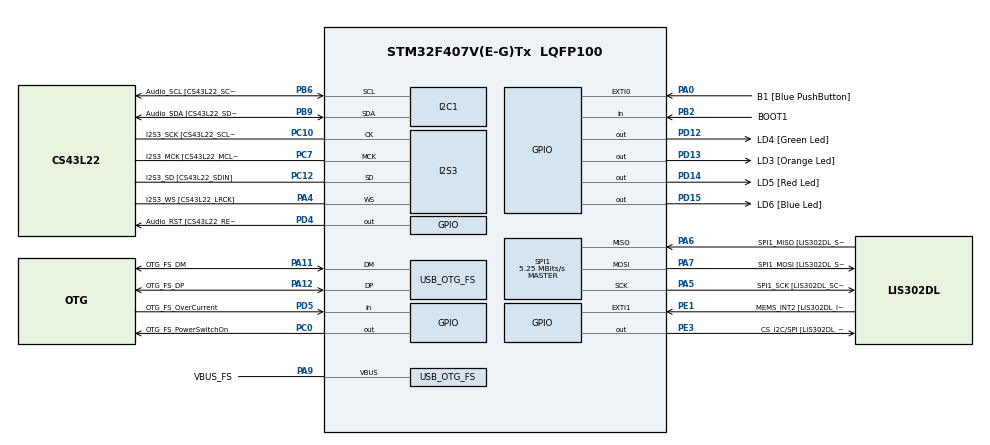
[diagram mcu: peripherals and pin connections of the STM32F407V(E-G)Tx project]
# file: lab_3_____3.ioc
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I2S3.AudioFreq-Half_Duplex_Master=I2S_AUDIOFREQ_96K
I2S3.ErrorAudioFreq=-2.34 %
I2S3.ErrorAudioFreq-Half_Duplex_Master=0.8 %
I2S3.FullDuplexMode=I2S_FULLDUPLEXMODE_DISABLE
I2S3.Instance=SPI$Index
I2S3.RealAudioFreq=93.75 KHz
I2S3.RealAudioFreq-Half_Duplex_Master=96.774 KHz
I2S3.VirtualMode=I2S_MODE_MASTER
Mcu.Family=STM32F4
Mcu.Name=STM32F407V(E-G)Tx
Mcu.Package=LQFP100
NVIC.OTG_FS_IRQn=true\:0\:0\:false\:false\:true\:true\:true
NVIC.PriorityGroup=NVIC_PRIORITYGROUP_0
NVIC.TIM2_IRQn=true\:0\:0\:false\:false\:true\:true\:true
NVIC.TIM3_IRQn=true\:0\:0\:false\:false\:true\:true\:true
NVIC.TIM4_IRQn=true\:0\:0\:false\:false\:true\:true\:true
PA0-WKUP.GPIO_Label=B1 [Blue PushButton]
PA0-WKUP.GPIO_ModeDefaultEXTI=GPIO_MODE_EVT_RISING
PA0-WKUP.GPIO_PuPd=GPIO_NOPULL
PA0-WKUP.Signal=GPXTI0
PA10.GPIO_Label=OTG_FS_ID
PA10.GPIO_Mode=GPIO_MODE_AF_PP
PA10.GPIO_PuPd=GPIO_NOPULL
PA10.GPIO_Speed=GPIO_SPEED_FREQ_LOW
PA10.Signal=USB_OTG_FS_ID
PA11.GPIO_Label=OTG_FS_DM
PA11.GPIO_Mode=GPIO_MODE_AF_PP
PA11.GPIO_PuPd=GPIO_NOPULL
PA11.GPIO_Speed=GPIO_SPEED_FREQ_LOW
PA11.Mode=Host_Only
PA11.Signal=USB_OTG_FS_DM
PA12.GPIO_Label=OTG_FS_DP
PA12.GPIO_Mode=GPIO_MODE_AF_PP
PA12.GPIO_PuPd=GPIO_NOPULL
PA12.GPIO_Speed=GPIO_SPEED_FREQ_LOW
PA12.Mode=Host_Only
PA12.Signal=USB_OTG_FS_DP
PA13.GPIO_Label=SWDIO
PA13.Mode=Serial_Wire
PA13.Signal=SYS_JTMS-SWDIO
PA14.GPIO_Label=SWCLK
PA14.Mode=Serial_Wire
PA14.Signal=SYS_JTCK-SWCLK
PA4.GPIO_Label=I2S3_WS [CS43L22_LRCK]
PA4.GPIO_Mode=GPIO_MODE_AF_PP
PA4.GPIO_PuPd=GPIO_NOPULL
PA4.GPIO_Speed=GPIO_SPEED_FREQ_LOW
PA4.Mode=Half_Duplex_Master
PA4.Signal=I2S3_WS
PA5.GPIO_Label=SPI1_SCK [LIS302DL_SCL/SPC]
PA5.GPIO_Mode=GPIO_MODE_AF_PP
PA5.GPIO_PuPd=GPIO_NOPULL
PA5.GPIO_Speed=GPIO_SPEED_FREQ_LOW
PA5.Mode=Full_Duplex_Master
PA5.Signal=SPI1_SCK
PA6.GPIO_Label=SPI1_MISO [LIS302DL_SDO]
PA6.GPIO_Mode=GPIO_MODE_AF_PP
PA6.GPIO_PuPd=GPIO_NOPULL
PA6.GPIO_Speed=GPIO_SPEED_FREQ_LOW
PA6.Mode=Full_Duplex_Master
PA6.Signal=SPI1_MISO
PA7.GPIO_Label=SPI1_MOSI [LIS302DL_SDA/SDI/SDO]
PA7.GPIO_Mode=GPIO_MODE_AF_PP
PA7.GPIO_PuPd=GPIO_NOPULL
PA7.GPIO_Speed=GPIO_SPEED_FREQ_LOW
PA7.Mode=Full_Duplex_Master
PA7.Signal=SPI1_MOSI
PA9.GPIO_Label=VBUS_FS
PA9.GPIO_Mode=GPIO_MODE_INPUT
PA9.GPIO_PuPd=GPIO_NOPULL
PA9.Mode=Activate_VBUS
PA9.Signal=USB_OTG_FS_VBUS
PB10.GPIO_Label=CLK_IN [MP45DT02_CLK]
PB10.GPIO_Mode=GPIO_MODE_AF_PP
PB10.GPIO_PuPd=GPIO_NOPULL
PB10.GPIO_Speed=GPIO_SPEED_FREQ_LOW
PB10.Signal=I2S2_CK
PB2.GPIO_Label=BOOT1
PB2.GPIO_Mode=GPIO_MODE_INPUT
PB2.GPIO_PuPd=GPIO_NOPULL
PB2.Signal=GPIO_Input
PB3.GPIO_Label=SWO
PB3.Signal=SYS_JTDO-SWO
PB6.GPIO_Label=Audio_SCL [CS43L22_SCL]
PB6.GPIO_Mode=GPIO_MODE_AF_OD
PB6.GPIO_Pu=GPIO_PULLUP
PB6.GPIO_PuPd=GPIO_NOPULL
PB6.GPIO_Speed=GPIO_SPEED_FREQ_LOW
PB6.Mode=I2C
PB6.Signal=I2C1_SCL
PB9.GPIO_Label=Audio_SDA [CS43L22_SDA]
PB9.GPIO_Mode=GPIO_MODE_AF_OD
PB9.GPIO_Pu=GPIO_PULLUP
PB9.GPIO_PuPd=GPIO_NOPULL
PB9.GPIO_Speed=GPIO_SPEED_FREQ_LOW
PB9.Mode=I2C
PB9.Signal=I2C1_SDA
PC0.GPIO_Label=OTG_FS_PowerSwitchOn
PC0.GPIO_PuPd=GPIO_NOPULL
PC0.GPIO_Speed=GPIO_SPEED_FREQ_LOW
PC0.PinState=GPIO_PIN_SET
PC0.Signal=GPIO_Output
PC10.GPIO_Label=I2S3_SCK [CS43L22_SCLK]
PC10.GPIO_Mode=GPIO_MODE_AF_PP
PC10.GPIO_PuPd=GPIO_NOPULL
PC10.GPIO_Speed=GPIO_SPEED_FREQ_LOW
PC10.Mode=Half_Duplex_Master
PC10.Signal=I2S3_CK
PC12.GPIO_Label=I2S3_SD [CS43L22_SDIN]
PC12.GPIO_Mode=GPIO_MODE_AF_PP
PC12.GPIO_PuPd=GPIO_NOPULL
PC12.GPIO_Speed=GPIO_SPEED_FREQ_LOW
PC12.Mode=Half_Duplex_Master
PC12.Signal=I2S3_SD
PC14-OSC32_IN.GPIO_Label=PC14-OSC32_IN
PC14-OSC32_IN.Mode=LSE-External-Oscillator
PC14-OSC32_IN.Signal=RCC_OSC32_IN
PC15-OSC32_OUT.GPIO_Label=PC15-OSC32_OUT
PC15-OSC32_OUT.Mode=LSE-External-Oscillator
PC15-OSC32_OUT.Signal=RCC_OSC32_OUT
PC3.GPIO_Label=PDM_OUT [MP45DT02_DOUT]
PC3.GPIO_Mode=GPIO_MODE_AF_PP
PC3.GPIO_PuPd=GPIO_NOPULL
PC3.GPIO_Speed=GPIO_SPEED_FREQ_LOW
PC3.Signal=I2S2_SD
PC7.GPIO_Label=I2S3_MCK [CS43L22_MCLK]
PC7.GPIO_Mode=GPIO_MODE_AF_PP
PC7.GPIO_PuPd=GPIO_NOPULL
PC7.GPIO_Speed=GPIO_SPEED_FREQ_LOW
PC7.Mode=Master_Clock_Activated
PC7.Signal=I2S3_MCK
PD12.GPIO_Label=LD4 [Green Led]
PD12.GPIO_PuPd=GPIO_NOPULL
PD12.GPIO_Speed=GPIO_SPEED_FREQ_LOW
PD12.Signal=GPIO_Output
PD13.GPIO_Label=LD3 [Orange Led]
PD13.GPIO_PuPd=GPIO_NOPULL
PD13.GPIO_Speed=GPIO_SPEED_FREQ_LOW
PD13.Signal=GPIO_Output
PD14.GPIO_Label=LD5 [Red Led]
PD14.GPIO_PuPd=GPIO_NOPULL
PD14.GPIO_Speed=GPIO_SPEED_FREQ_LOW
PD14.Signal=GPIO_Output
PD15.GPIO_Label=LD6 [Blue Led]
PD15.GPIO_PuPd=GPIO_NOPULL
PD15.GPIO_Speed=GPIO_SPEED_FREQ_LOW
PD15.Signal=GPIO_Output
PD4.GPIO_Label=Audio_RST [CS43L22_RESET]
PD4.GPIO_PuPd=GPIO_NOPULL
PD4.GPIO_Speed=GPIO_SPEED_FREQ_LOW
PD4.Signal=GPIO_Output
PD5.GPIO_Label=OTG_FS_OverCurrent
PD5.GPIO_Mode=GPIO_MODE_INPUT
PD5.GPIO_PuPd=GPIO_NOPULL
PD5.Signal=GPIO_Input
PE1.GPIO_Label=MEMS_INT2 [LIS302DL_INT2]
PE1.GPIO_ModeDefaultEXTI=GPIO_MODE_EVT_RISING
PE1.GPIO_PuPd=GPIO_NOPULL
PE1.Signal=GPXTI1
PE3.GPIO_Label=CS_I2C/SPI [LIS302DL_CS_I2C/SPI]
PE3.GPIO_PuPd=GPIO_NOPULL
PE3.GPIO_Speed=GPIO_SPEED_FREQ_LOW
PE3.Signal=GPIO_Output
PH0-OSC_IN.GPIO_Label=PH0-OSC_IN
PH0-OSC_IN.Mode=HSE-External-Oscillator
PH0-OSC_IN.Signal=RCC_OSC_IN
PH1-OSC_OUT.GPIO_Label=PH1-OSC_OUT
PH1-OSC_OUT.Mode=HSE-External-Oscillator
PH1-OSC_OUT.Signal=RCC_OSC_OUT
ProjectManager.HeapSize=0x200
ProjectManager.StackSize=0x400
ProjectManager.TargetToolchain=STM32CubeIDE
RCC.48MHZClocksFreq_Value=48000000
RCC.AHBCLKDivider=RCC_SYSCLK_DIV8
RCC.AHBFreq_Value=21000000
RCC.APB1CLKDivider=RCC_HCLK_DIV4
RCC.APB1Freq_Value=5250000
RCC.APB1TimFreq_Value=10500000
RCC.APB2CLKDivider=RCC_HCLK_DIV2
RCC.APB2Freq_Value=10500000
RCC.APB2TimFreq_Value=21000000
RCC.CortexFreq_Value=21000000
RCC.HCLKFreq_Value=21000000
RCC.HSE_VALUE=8000000
RCC.HSI_VALUE=16000000
RCC.PLLM=8
RCC.PLLQ=7
RCC.SYSCLKFreq_VALUE=168000000
RCC.SYSCLKSource=RCC_SYSCLKSOURCE_PLLCLK
RCC.VCOOutputFreq_Value=336000000
SPI1.BaudRatePrescaler-Full_Duplex_Master=SPI_BAUDRATEPRESCALER_2
SPI1.CalculateBaudRate=5.25 MBits/s
SPI1.CalculateBaudRate-Full_Duplex_Master=42.0 MBits/s
SPI1.Direction=SPI_DIRECTION_2LINES
SPI1.Mode=SPI_MODE_MASTER
SPI1.Mode-Full_Duplex_Master=SPI_MODE_MASTER
SPI1.VirtualType=VM_MASTER
TIM2.AutoReloadPreload=TIM_AUTORELOAD_PRELOAD_ENABLE
TIM2.Period=210
TIM2.Prescaler=25000
TIM3.AutoReloadPreload=TIM_AUTORELOAD_PRELOAD_ENABLE
TIM3.Period=210
TIM3.Prescaler=24525
TIM4.AutoReloadPreload=TIM_AUTORELOAD_PRELOAD_ENABLE
TIM4.Period=210
TIM4.Prescaler=49950
USB_HOST.BSP.number=1
USB_HOST.USBH_HandleTypeDef-CDC_FS=hUsbHostFS
USB_HOST.VirtualModeFS=Cdc
USB_HOST0.BSP.STBoard=false
USB_HOST0.BSP.api=Unknown
USB_HOST0.BSP.i2caddr=0
USB_HOST0.BSP.i2creg=0
USB_HOST0.BSP.instance=PC0
USB_HOST0.BSP.ip=GPIO
USB_HOST0.BSP.mode=Output
USB_HOST0.BSP.name=Drive_VBUS_FS
USB_HOST0.BSP.solution=PC0
USB_OTG_FS.VirtualMode=Host_Only
USB_OTG_FS.phy_itface=HCD_PHY_EMBEDDED
VP_TIM2_VS_ClockSourceINT.Mode=Internal
VP_TIM3_VS_ClockSourceINT.Mode=Internal
VP_TIM4_VS_ClockSourceINT.Mode=Internal
VP_USB_HOST_VS_USB_HOST_CDC_FS.Mode=CDC_FS
board=STM32F407G-DISC1

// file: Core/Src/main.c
/* USER CODE BEGIN Header */
/**
  ******************************************************************************
  * @file           : main.c
  * @brief          : Main program body
  ******************************************************************************
  * @attention
  *
  * Copyright (c) 2022 STMicroelectronics.
  * All rights reserved.
  *
  * This software is licensed under terms that can be found in the LICENSE file
  * in the root directory of this software component.
  * If no LICENSE file comes with this software, it is provided AS-IS.
  *
  ******************************************************************************
  */
/* USER CODE END Header */
#include "main.h"
#include "usb_host.h"

/* USER CODE BEGIN Includes */
#include "stdbool.h"
/* USER CODE END Includes */

I2C_HandleTypeDef hi2c1;

I2S_HandleTypeDef hi2s3;

SPI_HandleTypeDef hspi1;

TIM_HandleTypeDef htim2;
TIM_HandleTypeDef htim3;
TIM_HandleTypeDef htim4;

void SystemClock_Config(void);
static void MX_GPIO_Init(void);
static void MX_I2C1_Init(void);
static void MX_I2S3_Init(void);
static void MX_SPI1_Init(void);
static void MX_TIM2_Init(void);
static void MX_TIM3_Init(void);
static void MX_TIM4_Init(void);
void MX_USB_HOST_Process(void);

int main(void)
{

  /* MCU Configuration--------------------------------------------------------*/

  /* Reset of all peripherals, Initializes the Flash interface and the Systick. */
  HAL_Init();

  /* Configure the system clock */
  SystemClock_Config();

  /* Initialize all configured peripherals */
  MX_GPIO_Init();
  MX_I2C1_Init();
  MX_I2S3_Init();
  MX_SPI1_Init();
  MX_USB_HOST_Init();
  MX_TIM2_Init();
  MX_TIM3_Init();
  MX_TIM4_Init();
  /* USER CODE BEGIN 2 */
  HAL_TIM_Base_Start_IT(&htim2);
  HAL_TIM_Base_Start_IT(&htim3);
//  HAL_TIM_Base_Start_IT(&htim4);

  /* USER CODE END 2 */

  /* Infinite loop */
  while (1)
  {
    MX_USB_HOST_Process();

    /* USER CODE BEGIN 3 */
//    HAL_GPIO_WritePin(GPIOD, GPIO_PIN_14, GPIO_PIN_SET);
  }
  /* USER CODE END 3 */
}

void SystemClock_Config(void)
{
  RCC_OscInitTypeDef RCC_OscInitStruct = {0};
  RCC_ClkInitTypeDef RCC_ClkInitStruct = {0};

  /** Configure the main internal regulator output voltage
  */
  __HAL_RCC_PWR_CLK_ENABLE();
  __HAL_PWR_VOLTAGESCALING_CONFIG(PWR_REGULATOR_VOLTAGE_SCALE1);
  /** Initializes the RCC Oscillators according to the specified parameters
  * in the RCC_OscInitTypeDef structure.
  */
  RCC_OscInitStruct.OscillatorType = RCC_OSCILLATORTYPE_HSE;
  RCC_OscInitStruct.HSEState = RCC_HSE_ON;
  RCC_OscInitStruct.PLL.PLLState = RCC_PLL_ON;
  RCC_OscInitStruct.PLL.PLLSource = RCC_PLLSOURCE_HSE;
  RCC_OscInitStruct.PLL.PLLM = 8;
  RCC_OscInitStruct.PLL.PLLN = 192;
  RCC_OscInitStruct.PLL.PLLP = RCC_PLLP_DIV2;
  RCC_OscInitStruct.PLL.PLLQ = 7;
  if (HAL_RCC_OscConfig(&RCC_OscInitStruct) != HAL_OK)
  {
    Error_Handler();
  }
  /** Initializes the CPU, AHB and APB buses clocks
  */
  RCC_ClkInitStruct.ClockType = RCC_CLOCKTYPE_HCLK|RCC_CLOCKTYPE_SYSCLK
                              |RCC_CLOCKTYPE_PCLK1|RCC_CLOCKTYPE_PCLK2;
  RCC_ClkInitStruct.SYSCLKSource = RCC_SYSCLKSOURCE_PLLCLK;
  RCC_ClkInitStruct.AHBCLKDivider = RCC_SYSCLK_DIV8;
  RCC_ClkInitStruct.APB1CLKDivider = RCC_HCLK_DIV4;
  RCC_ClkInitStruct.APB2CLKDivider = RCC_HCLK_DIV2;

  if (HAL_RCC_ClockConfig(&RCC_ClkInitStruct, FLASH_LATENCY_0) != HAL_OK)
  {
    Error_Handler();
  }
}

static void MX_I2C1_Init(void)
{

  hi2c1.Instance = I2C1;
  hi2c1.Init.ClockSpeed = 100000;
  hi2c1.Init.DutyCycle = I2C_DUTYCYCLE_2;
  hi2c1.Init.OwnAddress1 = 0;
  hi2c1.Init.AddressingMode = I2C_ADDRESSINGMODE_7BIT;
  hi2c1.Init.DualAddressMode = I2C_DUALADDRESS_DISABLE;
  hi2c1.Init.OwnAddress2 = 0;
  hi2c1.Init.GeneralCallMode = I2C_GENERALCALL_DISABLE;
  hi2c1.Init.NoStretchMode = I2C_NOSTRETCH_DISABLE;
  if (HAL_I2C_Init(&hi2c1) != HAL_OK)
  {
    Error_Handler();
  }

}

static void MX_I2S3_Init(void)
{

  hi2s3.Instance = SPI3;
  hi2s3.Init.Mode = I2S_MODE_MASTER_TX;
  hi2s3.Init.Standard = I2S_STANDARD_PHILIPS;
  hi2s3.Init.DataFormat = I2S_DATAFORMAT_16B;
  hi2s3.Init.MCLKOutput = I2S_MCLKOUTPUT_ENABLE;
  hi2s3.Init.AudioFreq = I2S_AUDIOFREQ_96K;
  hi2s3.Init.CPOL = I2S_CPOL_LOW;
  hi2s3.Init.ClockSource = I2S_CLOCK_PLL;
  hi2s3.Init.FullDuplexMode = I2S_FULLDUPLEXMODE_DISABLE;
  if (HAL_I2S_Init(&hi2s3) != HAL_OK)
  {
    Error_Handler();
  }

}

static void MX_SPI1_Init(void)
{

  /* SPI1 parameter configuration*/
  hspi1.Instance = SPI1;
  hspi1.Init.Mode = SPI_MODE_MASTER;
  hspi1.Init.Direction = SPI_DIRECTION_2LINES;
  hspi1.Init.DataSize = SPI_DATASIZE_8BIT;
  hspi1.Init.CLKPolarity = SPI_POLARITY_LOW;
  hspi1.Init.CLKPhase = SPI_PHASE_1EDGE;
  hspi1.Init.NSS = SPI_NSS_SOFT;
  hspi1.Init.BaudRatePrescaler = SPI_BAUDRATEPRESCALER_2;
  hspi1.Init.FirstBit = SPI_FIRSTBIT_MSB;
  hspi1.Init.TIMode = SPI_TIMODE_DISABLE;
  hspi1.Init.CRCCalculation = SPI_CRCCALCULATION_DISABLE;
  hspi1.Init.CRCPolynomial = 10;
  if (HAL_SPI_Init(&hspi1) != HAL_OK)
  {
    Error_Handler();
  }

}

static void MX_TIM2_Init(void)
{

  TIM_ClockConfigTypeDef sClockSourceConfig = {0};
  TIM_MasterConfigTypeDef sMasterConfig = {0};

  htim2.Instance = TIM2;
  htim2.Init.Prescaler = 25000;
  htim2.Init.CounterMode = TIM_COUNTERMODE_UP;
  htim2.Init.Period = 210;
  htim2.Init.ClockDivision = TIM_CLOCKDIVISION_DIV1;
  htim2.Init.AutoReloadPreload = TIM_AUTORELOAD_PRELOAD_ENABLE;
  if (HAL_TIM_Base_Init(&htim2) != HAL_OK)
  {
    Error_Handler();
  }
  sClockSourceConfig.ClockSource = TIM_CLOCKSOURCE_INTERNAL;
  if (HAL_TIM_ConfigClockSource(&htim2, &sClockSourceConfig) != HAL_OK)
  {
    Error_Handler();
  }
  sMasterConfig.MasterOutputTrigger = TIM_TRGO_RESET;
  sMasterConfig.MasterSlaveMode = TIM_MASTERSLAVEMODE_DISABLE;
  if (HAL_TIMEx_MasterConfigSynchronization(&htim2, &sMasterConfig) != HAL_OK)
  {
    Error_Handler();
  }

}

static void MX_TIM3_Init(void)
{

  TIM_ClockConfigTypeDef sClockSourceConfig = {0};
  TIM_MasterConfigTypeDef sMasterConfig = {0};

  htim3.Instance = TIM3;
  htim3.Init.Prescaler = 24525;
  htim3.Init.CounterMode = TIM_COUNTERMODE_UP;
  htim3.Init.Period = 210;
  htim3.Init.ClockDivision = TIM_CLOCKDIVISION_DIV1;
  htim3.Init.AutoReloadPreload = TIM_AUTORELOAD_PRELOAD_ENABLE;
  if (HAL_TIM_Base_Init(&htim3) != HAL_OK)
  {
    Error_Handler();
  }
  sClockSourceConfig.ClockSource = TIM_CLOCKSOURCE_INTERNAL;
  if (HAL_TIM_ConfigClockSource(&htim3, &sClockSourceConfig) != HAL_OK)
  {
    Error_Handler();
  }
  sMasterConfig.MasterOutputTrigger = TIM_TRGO_RESET;
  sMasterConfig.MasterSlaveMode = TIM_MASTERSLAVEMODE_DISABLE;
  if (HAL_TIMEx_MasterConfigSynchronization(&htim3, &sMasterConfig) != HAL_OK)
  {
    Error_Handler();
  }

}

static void MX_TIM4_Init(void)
{

  TIM_ClockConfigTypeDef sClockSourceConfig = {0};
  TIM_MasterConfigTypeDef sMasterConfig = {0};

  htim4.Instance = TIM4;
  htim4.Init.Prescaler = 49950;
  htim4.Init.CounterMode = TIM_COUNTERMODE_UP;
  htim4.Init.Period = 210;
  htim4.Init.ClockDivision = TIM_CLOCKDIVISION_DIV1;
  htim4.Init.AutoReloadPreload = TIM_AUTORELOAD_PRELOAD_ENABLE;
  if (HAL_TIM_Base_Init(&htim4) != HAL_OK)
  {
    Error_Handler();
  }
  sClockSourceConfig.ClockSource = TIM_CLOCKSOURCE_INTERNAL;
  if (HAL_TIM_ConfigClockSource(&htim4, &sClockSourceConfig) != HAL_OK)
  {
    Error_Handler();
  }
  sMasterConfig.MasterOutputTrigger = TIM_TRGO_RESET;
  sMasterConfig.MasterSlaveMode = TIM_MASTERSLAVEMODE_DISABLE;
  if (HAL_TIMEx_MasterConfigSynchronization(&htim4, &sMasterConfig) != HAL_OK)
  {
    Error_Handler();
  }

}

static void MX_GPIO_Init(void)
{
  GPIO_InitTypeDef GPIO_InitStruct = {0};

  /* GPIO Ports Clock Enable */
  __HAL_RCC_GPIOE_CLK_ENABLE();
  __HAL_RCC_GPIOC_CLK_ENABLE();
  __HAL_RCC_GPIOH_CLK_ENABLE();
  __HAL_RCC_GPIOA_CLK_ENABLE();
  __HAL_RCC_GPIOB_CLK_ENABLE();
  __HAL_RCC_GPIOD_CLK_ENABLE();

  /*Configure GPIO pin Output Level */
  HAL_GPIO_WritePin(CS_I2C_SPI_GPIO_Port, CS_I2C_SPI_Pin, GPIO_PIN_RESET);

  /*Configure GPIO pin Output Level */
  HAL_GPIO_WritePin(OTG_FS_PowerSwitchOn_GPIO_Port, OTG_FS_PowerSwitchOn_Pin, GPIO_PIN_SET);

  /*Configure GPIO pin Output Level */
  HAL_GPIO_WritePin(GPIOD, LD4_Pin|LD3_Pin|LD5_Pin|LD6_Pin
                          |Audio_RST_Pin, GPIO_PIN_RESET);

  /*Configure GPIO pin : CS_I2C_SPI_Pin */
  GPIO_InitStruct.Pin = CS_I2C_SPI_Pin;
  GPIO_InitStruct.Mode = GPIO_MODE_OUTPUT_PP;
  GPIO_InitStruct.Pull = GPIO_NOPULL;
  GPIO_InitStruct.Speed = GPIO_SPEED_FREQ_LOW;
  HAL_GPIO_Init(CS_I2C_SPI_GPIO_Port, &GPIO_InitStruct);

  /*Configure GPIO pin : OTG_FS_PowerSwitchOn_Pin */
  GPIO_InitStruct.Pin = OTG_FS_PowerSwitchOn_Pin;
  GPIO_InitStruct.Mode = GPIO_MODE_OUTPUT_PP;
  GPIO_InitStruct.Pull = GPIO_NOPULL;
  GPIO_InitStruct.Speed = GPIO_SPEED_FREQ_LOW;
  HAL_GPIO_Init(OTG_FS_PowerSwitchOn_GPIO_Port, &GPIO_InitStruct);

  /*Configure GPIO pin : PDM_OUT_Pin */
  GPIO_InitStruct.Pin = PDM_OUT_Pin;
  GPIO_InitStruct.Mode = GPIO_MODE_AF_PP;
  GPIO_InitStruct.Pull = GPIO_NOPULL;
  GPIO_InitStruct.Speed = GPIO_SPEED_FREQ_LOW;
  GPIO_InitStruct.Alternate = GPIO_AF5_SPI2;
  HAL_GPIO_Init(PDM_OUT_GPIO_Port, &GPIO_InitStruct);

  /*Configure GPIO pin : B1_Pin */
  GPIO_InitStruct.Pin = B1_Pin;
  GPIO_InitStruct.Mode = GPIO_MODE_EVT_RISING;
  GPIO_InitStruct.Pull = GPIO_NOPULL;
  HAL_GPIO_Init(B1_GPIO_Port, &GPIO_InitStruct);

  /*Configure GPIO pin : BOOT1_Pin */
  GPIO_InitStruct.Pin = BOOT1_Pin;
  GPIO_InitStruct.Mode = GPIO_MODE_INPUT;
  GPIO_InitStruct.Pull = GPIO_NOPULL;
  HAL_GPIO_Init(BOOT1_GPIO_Port, &GPIO_InitStruct);

  /*Configure GPIO pin : CLK_IN_Pin */
  GPIO_InitStruct.Pin = CLK_IN_Pin;
  GPIO_InitStruct.Mode = GPIO_MODE_AF_PP;
  GPIO_InitStruct.Pull = GPIO_NOPULL;
  GPIO_InitStruct.Speed = GPIO_SPEED_FREQ_LOW;
  GPIO_InitStruct.Alternate = GPIO_AF5_SPI2;
  HAL_GPIO_Init(CLK_IN_GPIO_Port, &GPIO_InitStruct);

  /*Configure GPIO pins : LD4_Pin LD3_Pin LD5_Pin LD6_Pin
                           Audio_RST_Pin */
  GPIO_InitStruct.Pin = LD4_Pin|LD3_Pin|LD5_Pin|LD6_Pin
                          |Audio_RST_Pin;
  GPIO_InitStruct.Mode = GPIO_MODE_OUTPUT_PP;
  GPIO_InitStruct.Pull = GPIO_NOPULL;
  GPIO_InitStruct.Speed = GPIO_SPEED_FREQ_LOW;
  HAL_GPIO_Init(GPIOD, &GPIO_InitStruct);

  /*Configure GPIO pin : OTG_FS_OverCurrent_Pin */
  GPIO_InitStruct.Pin = OTG_FS_OverCurrent_Pin;
  GPIO_InitStruct.Mode = GPIO_MODE_INPUT;
  GPIO_InitStruct.Pull = GPIO_NOPULL;
  HAL_GPIO_Init(OTG_FS_OverCurrent_GPIO_Port, &GPIO_InitStruct);

  /*Configure GPIO pin : MEMS_INT2_Pin */
  GPIO_InitStruct.Pin = MEMS_INT2_Pin;
  GPIO_InitStruct.Mode = GPIO_MODE_EVT_RISING;
  GPIO_InitStruct.Pull = GPIO_NOPULL;
  HAL_GPIO_Init(MEMS_INT2_GPIO_Port, &GPIO_InitStruct);

}

/* USER CODE BEGIN 4 */
void HAL_TIM_PeriodElapsedCallback(TIM_HandleTypeDef* htim)
{
//	HAL_GPIO_WritePin(GPIOD, GPIO_PIN_14, GPIO_PIN_SET);
	if (htim == &htim2) {

		HAL_GPIO_TogglePin(GPIOD, GPIO_PIN_14);
	} else if (htim == &htim3) {
		HAL_GPIO_TogglePin(GPIOD, GPIO_PIN_12);
	}
}

/* USER CODE END 4 */

void Error_Handler(void)
{
  __disable_irq();
  while (1)
  {
  }
}
